VERSION 5.7 ;
  NOWIREEXTENSIONATPIN ON ;
  DIVIDERCHAR "/" ;
  BUSBITCHARS "[]" ;
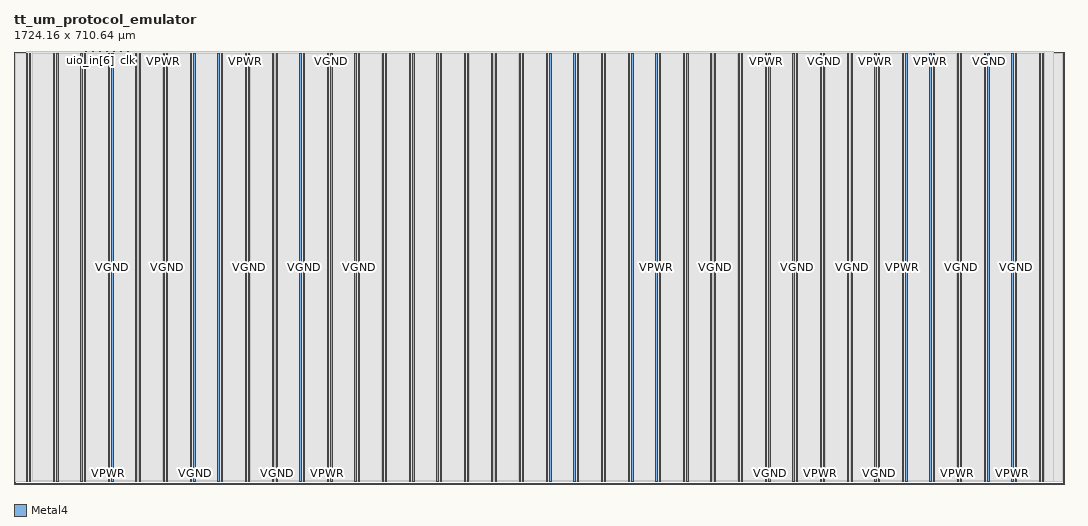
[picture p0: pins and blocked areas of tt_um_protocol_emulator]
MACRO tt_um_protocol_emulator
  CLASS BLOCK ;
  FOREIGN tt_um_protocol_emulator ;
  ORIGIN 0.000 0.000 ;
  SIZE 1724.160 BY 710.640 ;
  PIN VGND
    DIRECTION INOUT ;
    USE GROUND ;
    PORT
      LAYER Metal4 ;
        RECT 1644.170 3.560 1646.270 707.080 ;
    END
  END VGND
  PIN VGND
    DIRECTION INOUT ;
    USE GROUND ;
    PORT
      LAYER Metal4 ;
        RECT 1599.210 3.560 1601.310 707.080 ;
    END
  END VGND
  PIN VGND
    DIRECTION INOUT ;
    USE GROUND ;
    PORT
      LAYER Metal4 ;
        RECT 1554.250 3.560 1556.350 707.080 ;
    END
  END VGND
  PIN VGND
    DIRECTION INOUT ;
    USE GROUND ;
    PORT
      LAYER Metal4 ;
        RECT 1509.290 3.560 1511.390 707.080 ;
    END
  END VGND
  PIN VGND
    DIRECTION INOUT ;
    USE GROUND ;
    PORT
      LAYER Metal4 ;
        RECT 1464.330 3.560 1466.430 707.080 ;
    END
  END VGND
  PIN VGND
    DIRECTION INOUT ;
    USE GROUND ;
    PORT
      LAYER Metal4 ;
        RECT 1419.370 3.560 1421.470 707.080 ;
    END
  END VGND
  PIN VGND
    DIRECTION INOUT ;
    USE GROUND ;
    PORT
      LAYER Metal4 ;
        RECT 1374.410 3.560 1376.510 707.080 ;
    END
  END VGND
  PIN VGND
    DIRECTION INOUT ;
    USE GROUND ;
    PORT
      LAYER Metal4 ;
        RECT 1329.450 3.560 1331.550 707.080 ;
    END
  END VGND
  PIN VGND
    DIRECTION INOUT ;
    USE GROUND ;
    PORT
      LAYER Metal4 ;
        RECT 1284.490 3.560 1286.590 707.080 ;
    END
  END VGND
  PIN VGND
    DIRECTION INOUT ;
    USE GROUND ;
    PORT
      LAYER Metal4 ;
        RECT 1239.530 3.560 1241.630 707.080 ;
    END
  END VGND
  PIN VGND
    DIRECTION INOUT ;
    USE GROUND ;
    PORT
      LAYER Metal4 ;
        RECT 565.130 3.560 567.230 707.080 ;
    END
  END VGND
  PIN VGND
    DIRECTION INOUT ;
    USE GROUND ;
    PORT
      LAYER Metal4 ;
        RECT 520.170 3.560 522.270 707.080 ;
    END
  END VGND
  PIN VGND
    DIRECTION INOUT ;
    USE GROUND ;
    PORT
      LAYER Metal4 ;
        RECT 475.210 3.560 477.310 707.080 ;
    END
  END VGND
  PIN VGND
    DIRECTION INOUT ;
    USE GROUND ;
    PORT
      LAYER Metal4 ;
        RECT 430.250 3.560 432.350 707.080 ;
    END
  END VGND
  PIN VGND
    DIRECTION INOUT ;
    USE GROUND ;
    PORT
      LAYER Metal4 ;
        RECT 385.290 3.560 387.390 707.080 ;
    END
  END VGND
  PIN VGND
    DIRECTION INOUT ;
    USE GROUND ;
    PORT
      LAYER Metal4 ;
        RECT 340.330 3.560 342.430 707.080 ;
    END
  END VGND
  PIN VGND
    DIRECTION INOUT ;
    USE GROUND ;
    PORT
      LAYER Metal4 ;
        RECT 295.370 3.560 297.470 707.080 ;
    END
  END VGND
  PIN VGND
    DIRECTION INOUT ;
    USE GROUND ;
    PORT
      LAYER Metal4 ;
        RECT 250.410 3.560 252.510 707.080 ;
    END
  END VGND
  PIN VGND
    DIRECTION INOUT ;
    USE GROUND ;
    PORT
      LAYER Metal4 ;
        RECT 205.450 3.560 207.550 707.080 ;
    END
  END VGND
  PIN VGND
    DIRECTION INOUT ;
    USE GROUND ;
    PORT
      LAYER Metal4 ;
        RECT 160.490 3.560 162.590 707.080 ;
    END
  END VGND
  PIN VGND
    DIRECTION INOUT ;
    USE GROUND ;
    PORT
      LAYER Metal4 ;
        RECT 25.610 3.560 27.710 707.080 ;
    END
    PORT
      LAYER Metal4 ;
        RECT 70.570 3.560 72.670 707.080 ;
    END
    PORT
      LAYER Metal4 ;
        RECT 115.530 3.560 117.630 707.080 ;
    END
    PORT
      LAYER Metal4 ;
        RECT 610.090 3.560 612.190 707.080 ;
    END
    PORT
      LAYER Metal4 ;
        RECT 655.050 3.560 657.150 707.080 ;
    END
    PORT
      LAYER Metal4 ;
        RECT 700.010 3.560 702.110 707.080 ;
    END
    PORT
      LAYER Metal4 ;
        RECT 744.970 3.560 747.070 707.080 ;
    END
    PORT
      LAYER Metal4 ;
        RECT 789.930 3.560 792.030 707.080 ;
    END
    PORT
      LAYER Metal4 ;
        RECT 834.890 3.560 836.990 707.080 ;
    END
    PORT
      LAYER Metal4 ;
        RECT 879.850 3.560 881.950 707.080 ;
    END
    PORT
      LAYER Metal4 ;
        RECT 924.810 3.560 926.910 707.080 ;
    END
    PORT
      LAYER Metal4 ;
        RECT 969.770 3.560 971.870 707.080 ;
    END
    PORT
      LAYER Metal4 ;
        RECT 1014.730 3.560 1016.830 707.080 ;
    END
    PORT
      LAYER Metal4 ;
        RECT 1059.690 3.560 1061.790 707.080 ;
    END
    PORT
      LAYER Metal4 ;
        RECT 1104.650 3.560 1106.750 707.080 ;
    END
    PORT
      LAYER Metal4 ;
        RECT 1149.610 3.560 1151.710 707.080 ;
    END
    PORT
      LAYER Metal4 ;
        RECT 1194.570 3.560 1196.670 707.080 ;
    END
    PORT
      LAYER Metal4 ;
        RECT 1689.130 3.560 1691.230 707.080 ;
    END
  END VGND
  PIN VPWR
    DIRECTION INOUT ;
    USE POWER ;
    PORT
      LAYER Metal4 ;
        RECT 1638.550 3.560 1640.650 707.080 ;
    END
  END VPWR
  PIN VPWR
    DIRECTION INOUT ;
    USE POWER ;
    PORT
      LAYER Metal4 ;
        RECT 1593.590 3.560 1595.690 707.080 ;
    END
  END VPWR
  PIN VPWR
    DIRECTION INOUT ;
    USE POWER ;
    PORT
      LAYER Metal4 ;
        RECT 1548.630 3.560 1550.730 707.080 ;
    END
  END VPWR
  PIN VPWR
    DIRECTION INOUT ;
    USE POWER ;
    PORT
      LAYER Metal4 ;
        RECT 1503.670 3.560 1505.770 707.080 ;
    END
  END VPWR
  PIN VPWR
    DIRECTION INOUT ;
    USE POWER ;
    PORT
      LAYER Metal4 ;
        RECT 1458.710 3.560 1460.810 707.080 ;
    END
  END VPWR
  PIN VPWR
    DIRECTION INOUT ;
    USE POWER ;
    PORT
      LAYER Metal4 ;
        RECT 1413.750 3.560 1415.850 707.080 ;
    END
  END VPWR
  PIN VPWR
    DIRECTION INOUT ;
    USE POWER ;
    PORT
      LAYER Metal4 ;
        RECT 1368.790 3.560 1370.890 707.080 ;
    END
  END VPWR
  PIN VPWR
    DIRECTION INOUT ;
    USE POWER ;
    PORT
      LAYER Metal4 ;
        RECT 1323.830 3.560 1325.930 707.080 ;
    END
  END VPWR
  PIN VPWR
    DIRECTION INOUT ;
    USE POWER ;
    PORT
      LAYER Metal4 ;
        RECT 1278.870 3.560 1280.970 707.080 ;
    END
  END VPWR
  PIN VPWR
    DIRECTION INOUT ;
    USE POWER ;
    PORT
      LAYER Metal4 ;
        RECT 1233.910 3.560 1236.010 707.080 ;
    END
  END VPWR
  PIN VPWR
    DIRECTION INOUT ;
    USE POWER ;
    PORT
      LAYER Metal4 ;
        RECT 559.510 3.560 561.610 707.080 ;
    END
  END VPWR
  PIN VPWR
    DIRECTION INOUT ;
    USE POWER ;
    PORT
      LAYER Metal4 ;
        RECT 514.550 3.560 516.650 707.080 ;
    END
  END VPWR
  PIN VPWR
    DIRECTION INOUT ;
    USE POWER ;
    PORT
      LAYER Metal4 ;
        RECT 469.590 3.560 471.690 707.080 ;
    END
  END VPWR
  PIN VPWR
    DIRECTION INOUT ;
    USE POWER ;
    PORT
      LAYER Metal4 ;
        RECT 424.630 3.560 426.730 707.080 ;
    END
  END VPWR
  PIN VPWR
    DIRECTION INOUT ;
    USE POWER ;
    PORT
      LAYER Metal4 ;
        RECT 379.670 3.560 381.770 707.080 ;
    END
  END VPWR
  PIN VPWR
    DIRECTION INOUT ;
    USE POWER ;
    PORT
      LAYER Metal4 ;
        RECT 334.710 3.560 336.810 707.080 ;
    END
  END VPWR
  PIN VPWR
    DIRECTION INOUT ;
    USE POWER ;
    PORT
      LAYER Metal4 ;
        RECT 289.750 3.560 291.850 707.080 ;
    END
  END VPWR
  PIN VPWR
    DIRECTION INOUT ;
    USE POWER ;
    PORT
      LAYER Metal4 ;
        RECT 244.790 3.560 246.890 707.080 ;
    END
  END VPWR
  PIN VPWR
    DIRECTION INOUT ;
    USE POWER ;
    PORT
      LAYER Metal4 ;
        RECT 199.830 3.560 201.930 707.080 ;
    END
  END VPWR
  PIN VPWR
    DIRECTION INOUT ;
    USE POWER ;
    PORT
      LAYER Metal4 ;
        RECT 154.870 3.560 156.970 707.080 ;
    END
  END VPWR
  PIN VPWR
    DIRECTION INOUT ;
    USE POWER ;
    PORT
      LAYER Metal4 ;
        RECT 19.990 3.560 22.090 707.080 ;
    END
    PORT
      LAYER Metal4 ;
        RECT 64.950 3.560 67.050 707.080 ;
    END
    PORT
      LAYER Metal4 ;
        RECT 109.910 3.560 112.010 707.080 ;
    END
    PORT
      LAYER Metal4 ;
        RECT 604.470 3.560 606.570 707.080 ;
    END
    PORT
      LAYER Metal4 ;
        RECT 649.430 3.560 651.530 707.080 ;
    END
    PORT
      LAYER Metal4 ;
        RECT 694.390 3.560 696.490 707.080 ;
    END
    PORT
      LAYER Metal4 ;
        RECT 739.350 3.560 741.450 707.080 ;
    END
    PORT
      LAYER Metal4 ;
        RECT 784.310 3.560 786.410 707.080 ;
    END
    PORT
      LAYER Metal4 ;
        RECT 829.270 3.560 831.370 707.080 ;
    END
    PORT
      LAYER Metal4 ;
        RECT 874.230 3.560 876.330 707.080 ;
    END
    PORT
      LAYER Metal4 ;
        RECT 919.190 3.560 921.290 707.080 ;
    END
    PORT
      LAYER Metal4 ;
        RECT 964.150 3.560 966.250 707.080 ;
    END
    PORT
      LAYER Metal4 ;
        RECT 1009.110 3.560 1011.210 707.080 ;
    END
    PORT
      LAYER Metal4 ;
        RECT 1054.070 3.560 1056.170 707.080 ;
    END
    PORT
      LAYER Metal4 ;
        RECT 1099.030 3.560 1101.130 707.080 ;
    END
    PORT
      LAYER Metal4 ;
        RECT 1143.990 3.560 1146.090 707.080 ;
    END
    PORT
      LAYER Metal4 ;
        RECT 1188.950 3.560 1191.050 707.080 ;
    END
    PORT
      LAYER Metal4 ;
        RECT 1683.510 3.560 1685.610 707.080 ;
    END
  END VPWR
  PIN clk
    DIRECTION INPUT ;
    USE SIGNAL ;
    ANTENNAGATEAREA 1.450800 ;
    ANTENNADIFFAREA 4.030800 ;
    PORT
      LAYER Metal4 ;
        RECT 187.050 709.640 187.350 710.640 ;
    END
  END clk
  PIN ena
    DIRECTION INPUT ;
    USE SIGNAL ;
    PORT
      LAYER Metal4 ;
        RECT 190.890 709.640 191.190 710.640 ;
    END
  END ena
  PIN rst_n
    DIRECTION INPUT ;
    USE SIGNAL ;
    ANTENNAGATEAREA 0.180700 ;
    PORT
      LAYER Metal4 ;
        RECT 183.210 709.640 183.510 710.640 ;
    END
  END rst_n
  PIN ui_in[0]
    DIRECTION INPUT ;
    USE SIGNAL ;
    ANTENNAGATEAREA 0.180700 ;
    PORT
      LAYER Metal4 ;
        RECT 179.370 709.640 179.670 710.640 ;
    END
  END ui_in[0]
  PIN ui_in[1]
    DIRECTION INPUT ;
    USE SIGNAL ;
    ANTENNAGATEAREA 0.180700 ;
    PORT
      LAYER Metal4 ;
        RECT 175.530 709.640 175.830 710.640 ;
    END
  END ui_in[1]
  PIN ui_in[2]
    DIRECTION INPUT ;
    USE SIGNAL ;
    ANTENNAGATEAREA 0.180700 ;
    PORT
      LAYER Metal4 ;
        RECT 171.690 709.640 171.990 710.640 ;
    END
  END ui_in[2]
  PIN ui_in[3]
    DIRECTION INPUT ;
    USE SIGNAL ;
    ANTENNAGATEAREA 0.180700 ;
    PORT
      LAYER Metal4 ;
        RECT 167.850 709.640 168.150 710.640 ;
    END
  END ui_in[3]
  PIN ui_in[4]
    DIRECTION INPUT ;
    USE SIGNAL ;
    ANTENNAGATEAREA 0.180700 ;
    PORT
      LAYER Metal4 ;
        RECT 164.010 709.640 164.310 710.640 ;
    END
  END ui_in[4]
  PIN ui_in[5]
    DIRECTION INPUT ;
    USE SIGNAL ;
    ANTENNAGATEAREA 0.180700 ;
    PORT
      LAYER Metal4 ;
        RECT 160.170 709.640 160.470 710.640 ;
    END
  END ui_in[5]
  PIN ui_in[6]
    DIRECTION INPUT ;
    USE SIGNAL ;
    ANTENNAGATEAREA 0.180700 ;
    PORT
      LAYER Metal4 ;
        RECT 156.330 709.640 156.630 710.640 ;
    END
  END ui_in[6]
  PIN ui_in[7]
    DIRECTION INPUT ;
    USE SIGNAL ;
    ANTENNAGATEAREA 0.180700 ;
    PORT
      LAYER Metal4 ;
        RECT 152.490 709.640 152.790 710.640 ;
    END
  END ui_in[7]
  PIN uio_in[0]
    DIRECTION INPUT ;
    USE SIGNAL ;
    ANTENNAGATEAREA 0.180700 ;
    PORT
      LAYER Metal4 ;
        RECT 148.650 709.640 148.950 710.640 ;
    END
  END uio_in[0]
  PIN uio_in[1]
    DIRECTION INPUT ;
    USE SIGNAL ;
    ANTENNAGATEAREA 0.180700 ;
    PORT
      LAYER Metal4 ;
        RECT 144.810 709.640 145.110 710.640 ;
    END
  END uio_in[1]
  PIN uio_in[2]
    DIRECTION INPUT ;
    USE SIGNAL ;
    ANTENNAGATEAREA 0.180700 ;
    PORT
      LAYER Metal4 ;
        RECT 140.970 709.640 141.270 710.640 ;
    END
  END uio_in[2]
  PIN uio_in[3]
    DIRECTION INPUT ;
    USE SIGNAL ;
    ANTENNAGATEAREA 0.180700 ;
    PORT
      LAYER Metal4 ;
        RECT 137.130 709.640 137.430 710.640 ;
    END
  END uio_in[3]
  PIN uio_in[4]
    DIRECTION INPUT ;
    USE SIGNAL ;
    ANTENNAGATEAREA 0.180700 ;
    PORT
      LAYER Metal4 ;
        RECT 133.290 709.640 133.590 710.640 ;
    END
  END uio_in[4]
  PIN uio_in[5]
    DIRECTION INPUT ;
    USE SIGNAL ;
    ANTENNAGATEAREA 0.180700 ;
    PORT
      LAYER Metal4 ;
        RECT 129.450 709.640 129.750 710.640 ;
    END
  END uio_in[5]
  PIN uio_in[6]
    DIRECTION INPUT ;
    USE SIGNAL ;
    ANTENNAGATEAREA 0.180700 ;
    PORT
      LAYER Metal4 ;
        RECT 125.610 709.640 125.910 710.640 ;
    END
  END uio_in[6]
  PIN uio_in[7]
    DIRECTION INPUT ;
    USE SIGNAL ;
    ANTENNAGATEAREA 0.180700 ;
    PORT
      LAYER Metal4 ;
        RECT 121.770 709.640 122.070 710.640 ;
    END
  END uio_in[7]
  PIN uio_oe[0]
    DIRECTION OUTPUT ;
    USE SIGNAL ;
    ANTENNADIFFAREA 0.708600 ;
    PORT
      LAYER Metal4 ;
        RECT 56.490 709.640 56.790 710.640 ;
    END
  END uio_oe[0]
  PIN uio_oe[1]
    DIRECTION OUTPUT ;
    USE SIGNAL ;
    ANTENNADIFFAREA 0.708600 ;
    PORT
      LAYER Metal4 ;
        RECT 52.650 709.640 52.950 710.640 ;
    END
  END uio_oe[1]
  PIN uio_oe[2]
    DIRECTION OUTPUT ;
    USE SIGNAL ;
    ANTENNADIFFAREA 0.708600 ;
    PORT
      LAYER Metal4 ;
        RECT 48.810 709.640 49.110 710.640 ;
    END
  END uio_oe[2]
  PIN uio_oe[3]
    DIRECTION OUTPUT ;
    USE SIGNAL ;
    ANTENNADIFFAREA 0.708600 ;
    PORT
      LAYER Metal4 ;
        RECT 44.970 709.640 45.270 710.640 ;
    END
  END uio_oe[3]
  PIN uio_oe[4]
    DIRECTION OUTPUT ;
    USE SIGNAL ;
    ANTENNADIFFAREA 0.708600 ;
    PORT
      LAYER Metal4 ;
        RECT 41.130 709.640 41.430 710.640 ;
    END
  END uio_oe[4]
  PIN uio_oe[5]
    DIRECTION OUTPUT ;
    USE SIGNAL ;
    ANTENNADIFFAREA 0.708600 ;
    PORT
      LAYER Metal4 ;
        RECT 37.290 709.640 37.590 710.640 ;
    END
  END uio_oe[5]
  PIN uio_oe[6]
    DIRECTION OUTPUT ;
    USE SIGNAL ;
    ANTENNADIFFAREA 0.708600 ;
    PORT
      LAYER Metal4 ;
        RECT 33.450 709.640 33.750 710.640 ;
    END
  END uio_oe[6]
  PIN uio_oe[7]
    DIRECTION OUTPUT ;
    USE SIGNAL ;
    ANTENNADIFFAREA 0.708600 ;
    PORT
      LAYER Metal4 ;
        RECT 29.610 709.640 29.910 710.640 ;
    END
  END uio_oe[7]
  PIN uio_out[0]
    DIRECTION OUTPUT ;
    USE SIGNAL ;
    ANTENNADIFFAREA 0.708600 ;
    PORT
      LAYER Metal4 ;
        RECT 87.210 709.640 87.510 710.640 ;
    END
  END uio_out[0]
  PIN uio_out[1]
    DIRECTION OUTPUT ;
    USE SIGNAL ;
    ANTENNADIFFAREA 0.708600 ;
    PORT
      LAYER Metal4 ;
        RECT 83.370 709.640 83.670 710.640 ;
    END
  END uio_out[1]
  PIN uio_out[2]
    DIRECTION OUTPUT ;
    USE SIGNAL ;
    ANTENNADIFFAREA 0.708600 ;
    PORT
      LAYER Metal4 ;
        RECT 79.530 709.640 79.830 710.640 ;
    END
  END uio_out[2]
  PIN uio_out[3]
    DIRECTION OUTPUT ;
    USE SIGNAL ;
    ANTENNADIFFAREA 0.708600 ;
    PORT
      LAYER Metal4 ;
        RECT 75.690 709.640 75.990 710.640 ;
    END
  END uio_out[3]
  PIN uio_out[4]
    DIRECTION OUTPUT ;
    USE SIGNAL ;
    ANTENNADIFFAREA 0.708600 ;
    PORT
      LAYER Metal4 ;
        RECT 71.850 709.640 72.150 710.640 ;
    END
  END uio_out[4]
  PIN uio_out[5]
    DIRECTION OUTPUT ;
    USE SIGNAL ;
    ANTENNADIFFAREA 0.708600 ;
    PORT
      LAYER Metal4 ;
        RECT 68.010 709.640 68.310 710.640 ;
    END
  END uio_out[5]
  PIN uio_out[6]
    DIRECTION OUTPUT ;
    USE SIGNAL ;
    ANTENNADIFFAREA 0.708600 ;
    PORT
      LAYER Metal4 ;
        RECT 64.170 709.640 64.470 710.640 ;
    END
  END uio_out[6]
  PIN uio_out[7]
    DIRECTION OUTPUT ;
    USE SIGNAL ;
    ANTENNADIFFAREA 0.708600 ;
    PORT
      LAYER Metal4 ;
        RECT 60.330 709.640 60.630 710.640 ;
    END
  END uio_out[7]
  PIN uo_out[0]
    DIRECTION OUTPUT ;
    USE SIGNAL ;
    ANTENNADIFFAREA 0.708600 ;
    PORT
      LAYER Metal4 ;
        RECT 117.930 709.640 118.230 710.640 ;
    END
  END uo_out[0]
  PIN uo_out[1]
    DIRECTION OUTPUT ;
    USE SIGNAL ;
    ANTENNADIFFAREA 0.708600 ;
    PORT
      LAYER Metal4 ;
        RECT 114.090 709.640 114.390 710.640 ;
    END
  END uo_out[1]
  PIN uo_out[2]
    DIRECTION OUTPUT ;
    USE SIGNAL ;
    ANTENNADIFFAREA 0.708600 ;
    PORT
      LAYER Metal4 ;
        RECT 110.250 709.640 110.550 710.640 ;
    END
  END uo_out[2]
  PIN uo_out[3]
    DIRECTION OUTPUT ;
    USE SIGNAL ;
    ANTENNADIFFAREA 0.708600 ;
    PORT
      LAYER Metal4 ;
        RECT 106.410 709.640 106.710 710.640 ;
    END
  END uo_out[3]
  PIN uo_out[4]
    DIRECTION OUTPUT ;
    USE SIGNAL ;
    ANTENNADIFFAREA 0.708600 ;
    PORT
      LAYER Metal4 ;
        RECT 102.570 709.640 102.870 710.640 ;
    END
  END uo_out[4]
  PIN uo_out[5]
    DIRECTION OUTPUT ;
    USE SIGNAL ;
    ANTENNADIFFAREA 0.708600 ;
    PORT
      LAYER Metal4 ;
        RECT 98.730 709.640 99.030 710.640 ;
    END
  END uo_out[5]
  PIN uo_out[6]
    DIRECTION OUTPUT ;
    USE SIGNAL ;
    ANTENNADIFFAREA 0.708600 ;
    PORT
      LAYER Metal4 ;
        RECT 94.890 709.640 95.190 710.640 ;
    END
  END uo_out[6]
  PIN uo_out[7]
    DIRECTION OUTPUT ;
    USE SIGNAL ;
    ANTENNADIFFAREA 0.708600 ;
    PORT
      LAYER Metal4 ;
        RECT 91.050 709.640 91.350 710.640 ;
    END
  END uo_out[7]
  OBS
      LAYER GatPoly ;
        RECT 2.880 3.630 1721.280 707.010 ;
      LAYER Metal1 ;
        RECT 2.880 3.560 1721.280 707.080 ;
      LAYER Metal2 ;
        RECT 20.120 3.635 1707.465 707.845 ;
      LAYER Metal3 ;
        RECT 20.075 3.680 1707.505 710.325 ;
      LAYER Metal4 ;
        RECT 30.120 709.430 33.240 710.365 ;
        RECT 33.960 709.430 37.080 710.365 ;
        RECT 37.800 709.430 40.920 710.365 ;
        RECT 41.640 709.430 44.760 710.365 ;
        RECT 45.480 709.430 48.600 710.365 ;
        RECT 49.320 709.430 52.440 710.365 ;
        RECT 53.160 709.430 56.280 710.365 ;
        RECT 57.000 709.430 60.120 710.365 ;
        RECT 60.840 709.430 63.960 710.365 ;
        RECT 64.680 709.430 67.800 710.365 ;
        RECT 68.520 709.430 71.640 710.365 ;
        RECT 72.360 709.430 75.480 710.365 ;
        RECT 76.200 709.430 79.320 710.365 ;
        RECT 80.040 709.430 83.160 710.365 ;
        RECT 83.880 709.430 87.000 710.365 ;
        RECT 87.720 709.430 90.840 710.365 ;
        RECT 91.560 709.430 94.680 710.365 ;
        RECT 95.400 709.430 98.520 710.365 ;
        RECT 99.240 709.430 102.360 710.365 ;
        RECT 103.080 709.430 106.200 710.365 ;
        RECT 106.920 709.430 110.040 710.365 ;
        RECT 110.760 709.430 113.880 710.365 ;
        RECT 114.600 709.430 117.720 710.365 ;
        RECT 118.440 709.430 121.560 710.365 ;
        RECT 122.280 709.430 125.400 710.365 ;
        RECT 126.120 709.430 129.240 710.365 ;
        RECT 129.960 709.430 133.080 710.365 ;
        RECT 133.800 709.430 136.920 710.365 ;
        RECT 137.640 709.430 140.760 710.365 ;
        RECT 141.480 709.430 144.600 710.365 ;
        RECT 145.320 709.430 148.440 710.365 ;
        RECT 149.160 709.430 152.280 710.365 ;
        RECT 153.000 709.430 156.120 710.365 ;
        RECT 156.840 709.430 159.960 710.365 ;
        RECT 160.680 709.430 163.800 710.365 ;
        RECT 164.520 709.430 167.640 710.365 ;
        RECT 168.360 709.430 171.480 710.365 ;
        RECT 172.200 709.430 175.320 710.365 ;
        RECT 176.040 709.430 179.160 710.365 ;
        RECT 179.880 709.430 183.000 710.365 ;
        RECT 183.720 709.430 186.840 710.365 ;
        RECT 187.560 709.430 190.680 710.365 ;
        RECT 191.400 709.430 1692.100 710.365 ;
        RECT 29.660 707.290 1692.100 709.430 ;
        RECT 29.660 6.155 64.740 707.290 ;
        RECT 67.260 6.155 70.360 707.290 ;
        RECT 72.880 6.155 109.700 707.290 ;
        RECT 112.220 6.155 115.320 707.290 ;
        RECT 117.840 6.155 154.660 707.290 ;
        RECT 157.180 6.155 160.280 707.290 ;
        RECT 162.800 6.155 199.620 707.290 ;
        RECT 202.140 6.155 205.240 707.290 ;
        RECT 207.760 6.155 244.580 707.290 ;
        RECT 247.100 6.155 250.200 707.290 ;
        RECT 252.720 6.155 289.540 707.290 ;
        RECT 292.060 6.155 295.160 707.290 ;
        RECT 297.680 6.155 334.500 707.290 ;
        RECT 337.020 6.155 340.120 707.290 ;
        RECT 342.640 6.155 379.460 707.290 ;
        RECT 381.980 6.155 385.080 707.290 ;
        RECT 387.600 6.155 424.420 707.290 ;
        RECT 426.940 6.155 430.040 707.290 ;
        RECT 432.560 6.155 469.380 707.290 ;
        RECT 471.900 6.155 475.000 707.290 ;
        RECT 477.520 6.155 514.340 707.290 ;
        RECT 516.860 6.155 519.960 707.290 ;
        RECT 522.480 6.155 559.300 707.290 ;
        RECT 561.820 6.155 564.920 707.290 ;
        RECT 567.440 6.155 604.260 707.290 ;
        RECT 606.780 6.155 609.880 707.290 ;
        RECT 612.400 6.155 649.220 707.290 ;
        RECT 651.740 6.155 654.840 707.290 ;
        RECT 657.360 6.155 694.180 707.290 ;
        RECT 696.700 6.155 699.800 707.290 ;
        RECT 702.320 6.155 739.140 707.290 ;
        RECT 741.660 6.155 744.760 707.290 ;
        RECT 747.280 6.155 784.100 707.290 ;
        RECT 786.620 6.155 789.720 707.290 ;
        RECT 792.240 6.155 829.060 707.290 ;
        RECT 831.580 6.155 834.680 707.290 ;
        RECT 837.200 6.155 874.020 707.290 ;
        RECT 876.540 6.155 879.640 707.290 ;
        RECT 882.160 6.155 918.980 707.290 ;
        RECT 921.500 6.155 924.600 707.290 ;
        RECT 927.120 6.155 963.940 707.290 ;
        RECT 966.460 6.155 969.560 707.290 ;
        RECT 972.080 6.155 1008.900 707.290 ;
        RECT 1011.420 6.155 1014.520 707.290 ;
        RECT 1017.040 6.155 1053.860 707.290 ;
        RECT 1056.380 6.155 1059.480 707.290 ;
        RECT 1062.000 6.155 1098.820 707.290 ;
        RECT 1101.340 6.155 1104.440 707.290 ;
        RECT 1106.960 6.155 1143.780 707.290 ;
        RECT 1146.300 6.155 1149.400 707.290 ;
        RECT 1151.920 6.155 1188.740 707.290 ;
        RECT 1191.260 6.155 1194.360 707.290 ;
        RECT 1196.880 6.155 1233.700 707.290 ;
        RECT 1236.220 6.155 1239.320 707.290 ;
        RECT 1241.840 6.155 1278.660 707.290 ;
        RECT 1281.180 6.155 1284.280 707.290 ;
        RECT 1286.800 6.155 1323.620 707.290 ;
        RECT 1326.140 6.155 1329.240 707.290 ;
        RECT 1331.760 6.155 1368.580 707.290 ;
        RECT 1371.100 6.155 1374.200 707.290 ;
        RECT 1376.720 6.155 1413.540 707.290 ;
        RECT 1416.060 6.155 1419.160 707.290 ;
        RECT 1421.680 6.155 1458.500 707.290 ;
        RECT 1461.020 6.155 1464.120 707.290 ;
        RECT 1466.640 6.155 1503.460 707.290 ;
        RECT 1505.980 6.155 1509.080 707.290 ;
        RECT 1511.600 6.155 1548.420 707.290 ;
        RECT 1550.940 6.155 1554.040 707.290 ;
        RECT 1556.560 6.155 1593.380 707.290 ;
        RECT 1595.900 6.155 1599.000 707.290 ;
        RECT 1601.520 6.155 1638.340 707.290 ;
        RECT 1640.860 6.155 1643.960 707.290 ;
        RECT 1646.480 6.155 1683.300 707.290 ;
        RECT 1685.820 6.155 1688.920 707.290 ;
        RECT 1691.440 6.155 1692.100 707.290 ;
  END
END tt_um_protocol_emulator
END LIBRARY

